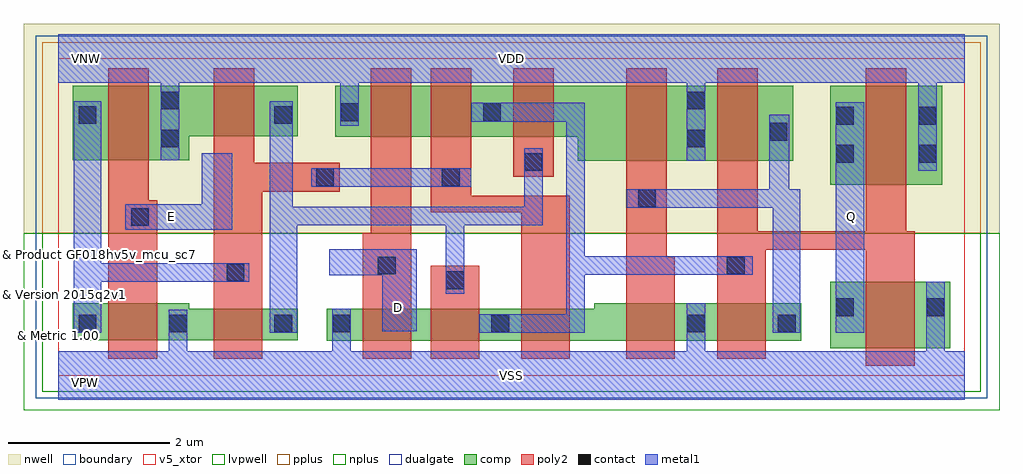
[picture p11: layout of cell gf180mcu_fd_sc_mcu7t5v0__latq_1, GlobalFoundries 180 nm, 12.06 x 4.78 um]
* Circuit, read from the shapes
.subckt gf180mcu_fd_sc_mcu7t5v0__latq_1 D E Q VDD VNW VSS
XM1 VSS E n1 VSUBS nfet_05v0 w=0.46u l=0.6u
XM2 n2 n1 VSS VSUBS nfet_05v0 w=0.39u l=0.6u
XM3 n3 D VSS VSUBS nfet_05v0 w=0.395u l=0.6u
XM4 n4 n2 n3 VSUBS nfet_05v0 w=0.395u l=0.6u
XM5 n5 n1 n4 VSUBS nfet_05v0 w=0.395u l=0.6u
XM6 VSS n6 n5 VSUBS nfet_05v0 w=0.465u l=0.6u
XM7 n6 n4 VSS VSUBS nfet_05v0 w=0.465u l=0.6u
XM8 VSS n4 Q VSUBS nfet_05v0 w=0.82u l=0.6u
XM9 VDD E n1 VNW pfet_05v0 w=0.92u l=0.5u
XM10 n2 n1 VDD VNW pfet_05v0 w=0.625u l=0.5u
XM11 n7 D VDD VNW pfet_05v0 w=0.63u l=0.5u
XM12 n4 n1 n7 VNW pfet_05v0 w=0.63u l=0.5u
XM13 n8 n2 n4 VNW pfet_05v0 w=0.63u l=0.5u
XM14 VDD n6 n8 VNW pfet_05v0 w=0.925u l=0.5u
XM15 n6 n4 VDD VNW pfet_05v0 w=0.925u l=0.5u
XM16 VDD n4 Q VNW pfet_05v0 w=1.22u l=0.5u
.ends

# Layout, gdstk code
import gdstk
lib = gdstk.Library(unit=1e-6, precision=1e-09)
def R(c, l, rs):  # rectangles x0, y0, x1, y1
    for r in rs: c.add(gdstk.rectangle(r[:2], r[2:], *l))
def P(c, l, *ps):  # polygons
    for p in ps: c.add(gdstk.Polygon(p, *l))
boundary = (0, 0)
nwell = (21, 0)
comp = (22, 0)
poly2 = (30, 0)
pplus = (31, 0)
nplus = (32, 0)
contact = (33, 0)
metal1 = (34, 0)
dualgate = (55, 0)
v5_xtor = (112, 1)
lvpwell = (204, 0)

gf180mcu_fd_sc_mcu7t5v0_ = lib.new_cell('gf180mcu_fd_sc_mcu7t5v0__latq_1')
R(gf180mcu_fd_sc_mcu7t5v0_, boundary, [(0,0,11.2,3.92)])
R(gf180mcu_fd_sc_mcu7t5v0_, nwell, [(-0.43,1.76,11.63,4.35)])
R(gf180mcu_fd_sc_mcu7t5v0_, comp, [(9.54,0.34,11.02,1.16), (9.54,2.36,10.92,3.58)])
P(gf180mcu_fd_sc_mcu7t5v0_, comp, [(0.18,0.435),(0.18,0.895),(1.62,0.895),(1.62,0.825),(2.96,0.825),(2.96,0.435)],
  [(0.18,2.66),(0.18,3.58),(2.96,3.58),(2.96,2.955),(1.62,2.955),(1.62,2.66)],
  [(6.42,2.655),(6.42,2.95),(3.42,2.95),(3.42,3.58),(9.08,3.58),(9.08,2.655)],
  [(3.32,0.43),(3.32,0.825),(6.62,0.825),(6.62,0.895),(9.18,0.895),(9.18,0.43)])
R(gf180mcu_fd_sc_mcu7t5v0_, poly2, [(4.6,0.21,5.2,1.36), (5.62,2.46,6.12,3.8)])
P(gf180mcu_fd_sc_mcu7t5v0_, poly2, [(0.62,0.21),(0.62,3.8),(1.12,3.8),(1.12,2.165),(1.22,2.165),(1.22,0.21)],
  [(1.92,0.21),(1.92,3.8),(2.42,3.8),(2.42,2.63),(3.475,2.63),(3.475,2.27),(2.52,2.27),(2.52,0.21)],
  [(3.76,0.21),(3.76,1.76),(3.86,1.76),(3.86,3.8),(4.36,3.8),(4.36,0.21)],
  [(5.72,0.21),(5.72,2.02),(4.6,2.02),(4.6,3.8),(5.1,3.8),(5.1,2.22),(6.32,2.22),(6.32,0.21)],
  [(7.02,0.21),(7.02,3.8),(7.52,3.8),(7.52,1.47),(7.62,1.47),(7.62,0.21)],
  [(9.98,0.12),(9.98,1.555),(8.74,1.555),(8.74,0.21),(8.14,0.21),(8.14,3.8),(8.64,3.8),(8.64,1.785),(9.98,1.785),(9.98,3.8),(10.48,3.8),(10.48,1.785),(10.58,1.785),(10.58,0.12)])
R(gf180mcu_fd_sc_mcu7t5v0_, pplus, [(-0.2,1.76,11.4,4.12)])
R(gf180mcu_fd_sc_mcu7t5v0_, nplus, [(-0.2,-0.2,11.4,1.76)])
R(gf180mcu_fd_sc_mcu7t5v0_, contact, [(0.25,0.535,0.47,0.755), (1.37,0.535,1.59,0.755), (2.67,0.535,2.89,0.755), (3.39,0.535,3.61,0.755), (5.35,0.535,5.57,0.755), (7.77,0.535,7.99,0.755), (8.89,0.535,9.11,0.755), (9.61,0.735,9.83,0.955), (10.73,0.735,10.95,0.955), (4.79,1.07,5.01,1.29), (2.08,1.165,2.3,1.385), (3.95,1.25,4.17,1.47), (8.26,1.25,8.48,1.47), (0.9,1.85,1.12,2.07), (7.165,2.08,7.385,2.3), (3.185,2.34,3.405,2.56), (4.74,2.34,4.96,2.56), (5.76,2.53,5.98,2.75), (9.61,2.63,9.83,2.85), (10.63,2.63,10.85,2.85), (1.27,2.82,1.49,3.04), (7.77,2.82,7.99,3.04), (8.79,2.905,9.01,3.125), (9.61,3.1,9.83,3.32), (10.63,3.1,10.85,3.32), (0.25,3.11,0.47,3.33), (2.67,3.11,2.89,3.33), (3.49,3.145,3.71,3.365), (5.25,3.145,5.47,3.365), (1.27,3.29,1.49,3.51), (7.77,3.29,7.99,3.51)])
R(gf180mcu_fd_sc_mcu7t5v0_, metal1, [(9.605,0.53,9.96,3.38), (3.125,2.335,5.1,2.565)])
P(gf180mcu_fd_sc_mcu7t5v0_, metal1, [(0.825,1.8),(0.825,2.12),(1.77,2.12),(1.77,2.75),(2.15,2.75),(2.15,1.8)],
  [(0.19,0.53),(0.19,3.39),(0.53,3.39),(0.53,1.39),(2.36,1.39),(2.36,1.16),(0.53,1.16),(0.53,0.53)],
  [(4,0.55),(4,1.24),(3.35,1.24),(3.35,1.56),(4.43,1.56),(4.43,0.55)],
  [(2.61,0.53),(2.61,3.39),(2.895,3.39),(2.895,2.085),(5.755,2.085),(5.755,2.81),(5.985,2.81),(5.985,1.855),(5.015,1.855),(5.015,1.01),(4.785,1.01),(4.785,1.855),(2.95,1.855),(2.95,0.53)],
  [(5.2,0.53),(5.2,0.76),(6.275,0.76),(6.275,3.14),(5.1,3.14),(5.1,3.37),(6.505,3.37),(6.505,1.475),(8.58,1.475),(8.58,1.245),(6.505,1.245),(6.505,0.53)],
  [(8.83,0.53),(8.83,2.075),(7.025,2.075),(7.025,2.305),(8.785,2.305),(8.785,3.225),(9.035,3.225),(9.035,2.305),(9.17,2.305),(9.17,0.53)],
  [(0,-0.3),(0,0.3),(1.365,0.3),(1.365,0.815),(1.595,0.815),(1.595,0.3),(3.385,0.3),(3.385,0.825),(3.615,0.825),(3.615,0.3),(7.765,0.3),(7.765,0.895),(7.995,0.895),(7.995,0.3),(10.725,0.3),(10.725,1.16),(10.955,1.16),(10.955,0.3),(11.2,0.3),(11.2,-0.3)],
  [(10.625,2.53),(10.625,3.62),(7.995,3.62),(7.995,2.655),(7.765,2.655),(7.765,3.62),(3.715,3.62),(3.715,3.085),(3.485,3.085),(3.485,3.62),(1.495,3.62),(1.495,2.66),(1.265,2.66),(1.265,3.62),(0,3.62),(0,4.22),(11.2,4.22),(11.2,3.62),(10.855,3.62),(10.855,2.53)])
R(gf180mcu_fd_sc_mcu7t5v0_, dualgate, [(-0.28,-0.28,11.48,4.2)])
R(gf180mcu_fd_sc_mcu7t5v0_, v5_xtor, [(0,0,11.2,3.92)])
R(gf180mcu_fd_sc_mcu7t5v0_, lvpwell, [(-0.43,-0.43,11.63,1.76)])
gf180mcu_fd_sc_mcu7t5v0_.add(gdstk.Label('Q', (9.8,1.96), layer=34, texttype=10))
gf180mcu_fd_sc_mcu7t5v0_.add(gdstk.Label('VDD', (5.6,3.92), layer=34, texttype=10))
gf180mcu_fd_sc_mcu7t5v0_.add(gdstk.Label('VSS', (5.6,0), layer=34, texttype=10))
gf180mcu_fd_sc_mcu7t5v0_.add(gdstk.Label('D', (4.2,0.84), layer=34, texttype=10))
gf180mcu_fd_sc_mcu7t5v0_.add(gdstk.Label('E', (1.4,1.96), layer=34, texttype=10))
gf180mcu_fd_sc_mcu7t5v0_.add(gdstk.Label('& Vendor GLOBALFOUNDRIES', (0,2), layer=63, texttype=63))
gf180mcu_fd_sc_mcu7t5v0_.add(gdstk.Label('& Product GF018hv5v_mcu_sc7', (0,1.5), layer=63, texttype=63))
gf180mcu_fd_sc_mcu7t5v0_.add(gdstk.Label('& Version 2015q2v1', (0,1), layer=63, texttype=63))
gf180mcu_fd_sc_mcu7t5v0_.add(gdstk.Label('& Metric 1.00', (0,0.5), layer=63, texttype=63))
gf180mcu_fd_sc_mcu7t5v0_.add(gdstk.Label('VNW', (0.345,3.92), layer=21, texttype=10))
gf180mcu_fd_sc_mcu7t5v0_.add(gdstk.Label('VPW', (0.34,-0.085), layer=204, texttype=10))

lib.write_gds('gf180mcu_fd_sc_mcu7t5v0__latq_1.gds')
